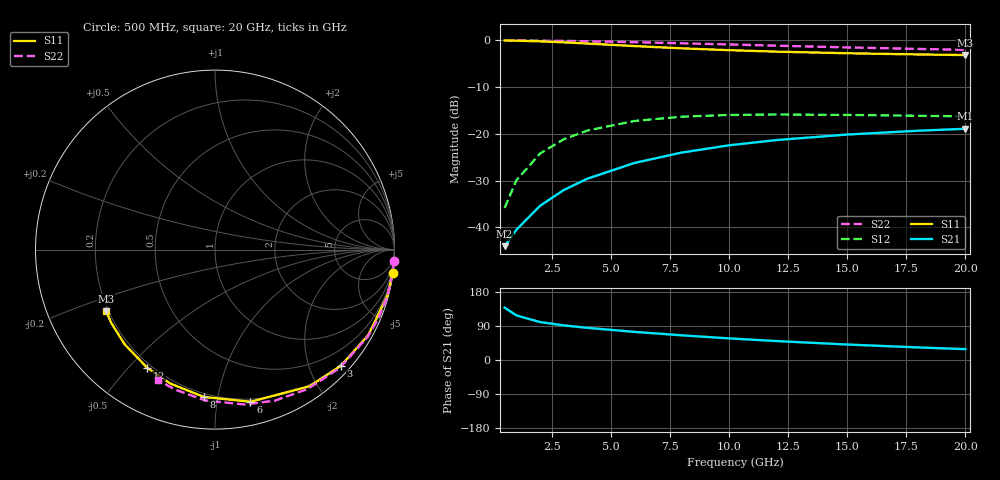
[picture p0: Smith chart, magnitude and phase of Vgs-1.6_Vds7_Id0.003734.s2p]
# Hz S RI R 50
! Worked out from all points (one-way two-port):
!   12 points, 500 MHz to 20 GHz, reference 50 ohm
!   highest |S21| = -18.90 dB at 20 GHz (marker M1); lowest = -44.0 dB at 500 MHz (marker M2)
!   lowest |S11| = -3.1 dB at 20 GHz (marker M3), VSWR 5.61, Z = 9.51 - j12.7 ohm
!   |S11| at or under -10 dB: nowhere
!   |S22| runs from -2.0 to 0.0 dB; largest |S21 - S12| = 0.12
!   S11 on the Smith chart (normalised r, x): 500 MHz: 0, -15; 3 GHz: 0.18, -2.55; 6 GHz: 0.18, -1.24; 8 GHz: 0.18, -0.91; 12 GHz: 0.18, -0.56; 20 GHz: 0.19, -0.25
5e8  0.9901 -0.1292  -0.0047 0.00419  0.00153 0.0161  0.9972 -0.0658
1e9  0.9611 -0.2541  -0.00437 0.00838  0.006 0.0314  0.9898 -0.131
2e9  0.8538 -0.4766  -0.003 0.0168  0.0224 0.0575  0.9605 -0.2578
3e9  0.701 -0.6471  -0.000581 0.0251  0.0451 0.0749  0.9137 -0.3766
4e9  0.5282 -0.761  0.00299 0.033  0.0698 0.0832  0.8515 -0.4847
6e9  0.1975 -0.8477  0.0133 0.0471  0.1129 0.0787  0.6947 -0.6598
8e9  -0.0628 -0.8207  0.0266 0.0573  0.1407 0.0598  0.5148 -0.7773
1e10  -0.2489 -0.746  0.0411 0.0634  0.1548 0.0382  0.3339 -0.8414
1.2e10  -0.3786 -0.6576  0.0553 0.0658  0.1601 0.0188  0.165 -0.8631
1.5e10  -0.5033 -0.5276  0.0745 0.0644  0.1596 -0.00369  -0.0527 -0.8407
1.8e10  -0.5763 -0.4117  0.0905 0.0592  0.1551 -0.0194  -0.2243 -0.7793
2e10  -0.6072 -0.3429  0.0996 0.0545  0.1515 -0.0272  -0.3157 -0.7271
